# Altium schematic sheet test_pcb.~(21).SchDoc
size A4; SheetNumber: 1; SheetTotal: 1

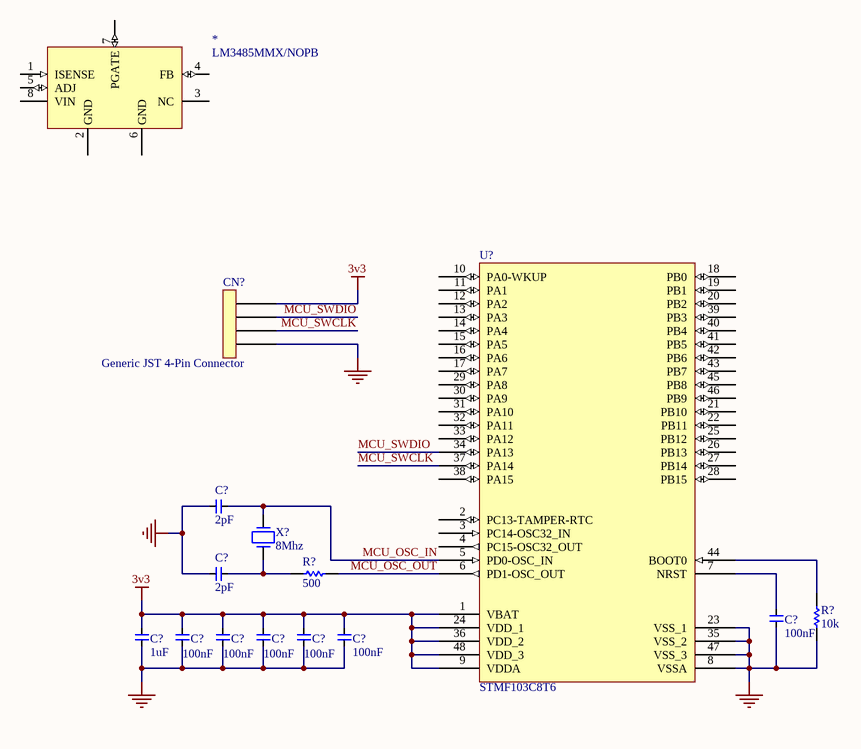
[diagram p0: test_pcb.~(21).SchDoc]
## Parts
(Parts that share a designator on the sheet are numbered #1, #2 ... from top to bottom, then left to right.)
*  LM3485MMX/NOPB
C?#1  2pF
C?#2  2pF
C?#3  100nF
C?#4  1uF
C?#5  100nF
C?#6  100nF
C?#7  100nF
C?#8  100nF
C?#9  100nF
CN?  Generic JST 4-Pin Connector
R?#1  500
R?#2  10k
U?  STMF103C8T6
X?  8Mhz

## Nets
3v3: C?#4.2 C?#5.2 C?#6.2 C?#7.2 C?#8.2 C?#9.2 CN?.1 U?.1(VBAT) U?.9(VDDA) U?.24(VDD_1) U?.36(VDD_2) U?.48(VDD_3)
GND: C?#1.1 C?#2.1 C?#3.1 C?#4.1 C?#5.1 C?#6.1 C?#7.1 C?#8.1 C?#9.1 CN?.4 R?#2.4 U?.8(VSSA) U?.23(VSS_1) U?.35(VSS_2) U?.47(VSS_3)
MCU_OSC_IN: C?#1.2 U?.5(PD0-OSC_IN) X?.2
MCU_OSC_OUT: R?#1.2 U?.6(PD1-OSC_OUT)
MCU_SWCLK: CN?.3 U?.37(PA14)
MCU_SWDIO: CN?.2 U?.34(PA13)
NetC?#2_2: C?#2.2 R?#1.4 X?.1
NetC?#3_2: C?#3.2 U?.7(NRST)
NetR?#2_2: R?#2.2 U?.44(BOOT0)

Not connected (* = marked no-connect by the designer): * 1(ISENSE) 2(GND) 3(NC) 4(FB) 5(ADJ) 6(GND) 7(PGATE) 8(VIN); U? 2(PC13-TAMPER-RTC) 3(PC14-OSC32_IN) 4(PC15-OSC32_OUT) 10(PA0-WKUP) 11(PA1) 12(PA2) 13(PA3) 14(PA4) 15(PA5) 16(PA6) 17(PA7) 18(PB0) 19(PB1) 20(PB2) 21(PB10) 22(PB11) 25(PB12) 26(PB13) 27(PB14) 28(PB15) 29(PA8) 30(PA9) 31(PA10) 32(PA11) 33(PA12) 38(PA15) 39(PB3) 40(PB4) 41(PB5) 42(PB6) 43(PB7) 45(PB8) 46(PB9)

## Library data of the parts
* = LM3485MMX/NOPB: Switching Controller, Voltage-mode, 0.1A, 1000kHz Switching Freq-Max, PDSO8; Manufacturer: TI National Semiconductor; Package Body Material: Plastic; Control Technique: HYSTERETIC CURRENT MODE; Max Supply Voltage: 35V; Min Input Voltage: 4.5V; Nominal Supply Voltage: 12V; Channels: 1; Max Output current: 100mA; Package Equivalence Code: TSSOP8,.19; Switcher Configuration: SINGLE; Frequency: 1MHz; Time @ Peak Reflow Temperature-Max (s): 40s; Qualification Status: Not Qualified
C?#1 C?#2 = GJM0335C1E2R0BB01D: Ceramic Capacitor, Multilayer, Ceramic, 25V, 5% +Tol, 5% -Tol, C0G, 30ppm/Cel TC, 0.000002uF, Surface Mount, 0201; Manufacturer: Murata; Multilayer: Yes
C?#3 C?#5-C?#9 = GRM033C80J104KE15D: Ceramic Capacitor, Multilayer, Ceramic, 6.3V, 10% +Tol, 10% -Tol, X6S, 22% TC, 0.1uF, Surface Mount, 0201; Manufacturer: Murata; Multilayer: Yes
C?#4 = GRM033R60J105MEA2D: Ceramic Capacitor, Multilayer, Ceramic, 6.3V, 20% +Tol, 20% -Tol, X5R, 15% TC, 1uF, Surface Mount, 0201; Manufacturer: Murata; Multilayer: Yes
R?#1 = ERA-2AEB4990X: Fixed Resistor, Thin Film, 0.063W, 499ohm, 50V, 0.1% +/-Tol, 25ppm/Cel, Surface Mount, 0402; Manufacturer: Panasonic; Power: 63mW; Rated Temperature: 85°C; Value: 499R; Working Voltage: 25V; Temperature Coefficient (ppm/Cel): 25; Package Height: 0.35mm; Package Length: 1mm; Package Width: 0.5mm; Reference Standard: AEC-Q200
R?#2 = RNCP1206FTD10K0: Fixed Resistor, Thin Film, 0.5W, 10000ohm, 200V, 1% +/-Tol, 100ppm/Cel, Surface Mount, 1206; Manufacturer: Stackpole Electronics; Additional Feature: ANTI-SULFUR; Power: 500mW; Rated Temperature: 70°C; Value: 10kR; Temperature Coefficient (ppm/Cel): 100; Package Height: 0.5mm; Package Length: 3.1mm; Package Width: 1.5mm
U? = STM32F103C8T6_1: ARM Cortex-M3 STM32 F1 Microcontroller 32-Bit 72MHz 64kB FLASH LQFP48 STM32F103C8T6; Manufacturer: STMicroelectronics; Package Body Material: Plastic; Clock Frequency: 16MHz; Number of I/O Lines: 37; Package Equivalence Code: QFP48,.35SQ,20; Power Supplies: 2.5/3.3; Max Supply Current: 50mA; Max Supply Voltage: 3.6V; Min Supply Voltage: 2V; Nominal Supply Voltage: 3.3V; Time @ Peak Reflow Temperature-Max (s): 30s; Peripherals: POR; Interface: I2C; Qualification Status: Not Qualified
X? = H130A-8.000-8-2030-TR: Parallel - Fundamental Quartz Crystal, 8MHz Min, 150MHz Max, 8MHz Nom; Manufacturer: Raltron Electronics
